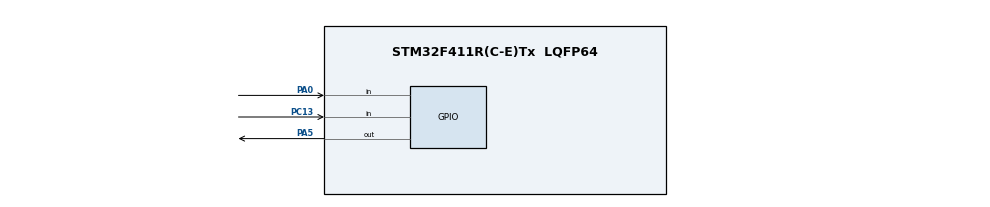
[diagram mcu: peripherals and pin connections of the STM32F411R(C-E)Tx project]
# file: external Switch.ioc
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Mcu.Family=STM32F4
Mcu.Name=STM32F411R(C-E)Tx
Mcu.Package=LQFP64
NVIC.PriorityGroup=NVIC_PRIORITYGROUP_0
PA0-WKUP.Signal=GPIO_Input
PA5.Signal=GPIO_Output
PC13-ANTI_TAMP.Signal=GPIO_Input
PC14-OSC32_IN.Mode=LSE-External-Oscillator
PC14-OSC32_IN.Signal=RCC_OSC32_IN
PC15-OSC32_OUT.Mode=LSE-External-Oscillator
PC15-OSC32_OUT.Signal=RCC_OSC32_OUT
ProjectManager.HeapSize=0x200
ProjectManager.StackSize=0x400
ProjectManager.TargetToolchain=STM32CubeIDE
board=NUCLEO-F411RE

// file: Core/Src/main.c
/* USER CODE BEGIN Header */
/**
  ******************************************************************************
  * @file           : main.c
  * @brief          : Main program body
  ******************************************************************************
  * @attention
  *
  * Copyright (c) 2025 STMicroelectronics.
  * All rights reserved.
  *
  * This software is licensed under terms that can be found in the LICENSE file
  * in the root directory of this software component.
  * If no LICENSE file comes with this software, it is provided AS-IS.
  *
  ******************************************************************************
  */
/* USER CODE END Header */
#include "main.h"

void SystemClock_Config(void);
static void MX_GPIO_Init(void);

int main(void)
{

  /* MCU Configuration--------------------------------------------------------*/

  /* Reset of all peripherals, Initializes the Flash interface and the Systick. */
  HAL_Init();

  /* Configure the system clock */
  SystemClock_Config();

  /* Initialize all configured peripherals */
  MX_GPIO_Init();

  /* Infinite loop */
  while (1)
  {
	  if(!(HAL_GPIO_ReadPin(GPIOA,GPIO_PIN_0))){
	 		  HAL_GPIO_WritePin(GPIOA,GPIO_PIN_5,SET);
	 	  }
	 		  else{
	 			  HAL_GPIO_WritePin(GPIOA,GPIO_PIN_5,RESET);
	 	  }

  }
}

void SystemClock_Config(void)
{
  RCC_OscInitTypeDef RCC_OscInitStruct = {0};
  RCC_ClkInitTypeDef RCC_ClkInitStruct = {0};

  /** Configure the main internal regulator output voltage
  */
  __HAL_RCC_PWR_CLK_ENABLE();
  __HAL_PWR_VOLTAGESCALING_CONFIG(PWR_REGULATOR_VOLTAGE_SCALE1);

  /** Initializes the RCC Oscillators according to the specified parameters
  * in the RCC_OscInitTypeDef structure.
  */
  RCC_OscInitStruct.OscillatorType = RCC_OSCILLATORTYPE_HSI;
  RCC_OscInitStruct.HSIState = RCC_HSI_ON;
  RCC_OscInitStruct.HSICalibrationValue = RCC_HSICALIBRATION_DEFAULT;
  RCC_OscInitStruct.PLL.PLLState = RCC_PLL_ON;
  RCC_OscInitStruct.PLL.PLLSource = RCC_PLLSOURCE_HSI;
  RCC_OscInitStruct.PLL.PLLM = 16;
  RCC_OscInitStruct.PLL.PLLN = 336;
  RCC_OscInitStruct.PLL.PLLP = RCC_PLLP_DIV4;
  RCC_OscInitStruct.PLL.PLLQ = 4;
  if (HAL_RCC_OscConfig(&RCC_OscInitStruct) != HAL_OK)
  {
    Error_Handler();
  }

  /** Initializes the CPU, AHB and APB buses clocks
  */
  RCC_ClkInitStruct.ClockType = RCC_CLOCKTYPE_HCLK|RCC_CLOCKTYPE_SYSCLK
                              |RCC_CLOCKTYPE_PCLK1|RCC_CLOCKTYPE_PCLK2;
  RCC_ClkInitStruct.SYSCLKSource = RCC_SYSCLKSOURCE_PLLCLK;
  RCC_ClkInitStruct.AHBCLKDivider = RCC_SYSCLK_DIV1;
  RCC_ClkInitStruct.APB1CLKDivider = RCC_HCLK_DIV2;
  RCC_ClkInitStruct.APB2CLKDivider = RCC_HCLK_DIV1;

  if (HAL_RCC_ClockConfig(&RCC_ClkInitStruct, FLASH_LATENCY_2) != HAL_OK)
  {
    Error_Handler();
  }
}

static void MX_GPIO_Init(void)
{
  GPIO_InitTypeDef GPIO_InitStruct = {0};

  /* GPIO Ports Clock Enable */
  __HAL_RCC_GPIOC_CLK_ENABLE();
  __HAL_RCC_GPIOA_CLK_ENABLE();

  /*Configure GPIO pin Output Level */
  HAL_GPIO_WritePin(GPIOA, GPIO_PIN_5, GPIO_PIN_RESET);

  /*Configure GPIO pin : PC13 */
  GPIO_InitStruct.Pin = GPIO_PIN_13;
  GPIO_InitStruct.Mode = GPIO_MODE_INPUT;
  GPIO_InitStruct.Pull = GPIO_NOPULL;
  HAL_GPIO_Init(GPIOC, &GPIO_InitStruct);

  /*Configure GPIO pin : PA0 */
  GPIO_InitStruct.Pin = GPIO_PIN_0;
  GPIO_InitStruct.Mode = GPIO_MODE_INPUT;
  GPIO_InitStruct.Pull = GPIO_NOPULL;
  HAL_GPIO_Init(GPIOA, &GPIO_InitStruct);

  /*Configure GPIO pin : PA5 */
  GPIO_InitStruct.Pin = GPIO_PIN_5;
  GPIO_InitStruct.Mode = GPIO_MODE_OUTPUT_PP;
  GPIO_InitStruct.Pull = GPIO_NOPULL;
  GPIO_InitStruct.Speed = GPIO_SPEED_FREQ_LOW;
  HAL_GPIO_Init(GPIOA, &GPIO_InitStruct);

}

void Error_Handler(void)
{
  __disable_irq();
  while (1)
  {
  }
}
